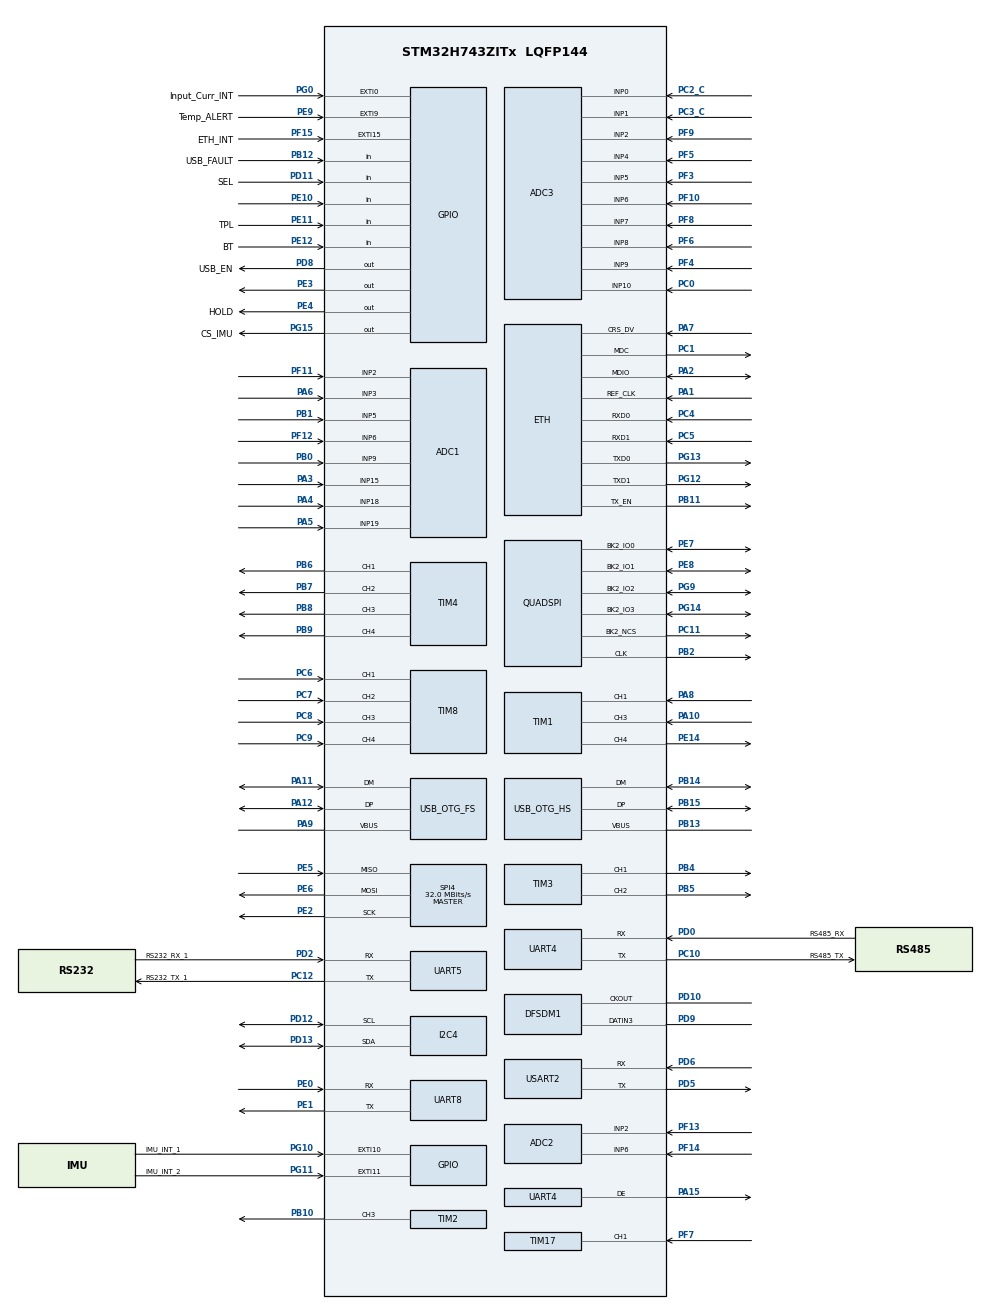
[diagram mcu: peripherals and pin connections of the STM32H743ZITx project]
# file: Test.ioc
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ADC1.Channel-13\#ChannelRegularConversion=ADC_CHANNEL_2
ADC1.NbrOfConversionFlag=1
ADC1.OffsetNumber-13\#ChannelRegularConversion=ADC_OFFSET_NONE
ADC1.OffsetSignedSaturation-13\#ChannelRegularConversion=DISABLE
ADC1.Rank-13\#ChannelRegularConversion=1
ADC1.SamplingTime-13\#ChannelRegularConversion=ADC_SAMPLETIME_1CYCLE_5
ADC1.master=1
ADC2.Channel-4\#ChannelRegularConversion=ADC_CHANNEL_2
ADC2.NbrOfConversionFlag=1
ADC2.OffsetNumber-4\#ChannelRegularConversion=ADC_OFFSET_NONE
ADC2.OffsetSignedSaturation-4\#ChannelRegularConversion=DISABLE
ADC2.Rank-4\#ChannelRegularConversion=1
ADC2.SamplingTime-4\#ChannelRegularConversion=ADC_SAMPLETIME_1CYCLE_5
ADC3.Channel-2\#ChannelRegularConversion=ADC_CHANNEL_2
ADC3.NbrOfConversionFlag=1
ADC3.OffsetNumber-2\#ChannelRegularConversion=ADC_OFFSET_NONE
ADC3.OffsetSignedSaturation-2\#ChannelRegularConversion=DISABLE
ADC3.Rank-2\#ChannelRegularConversion=1
ADC3.SamplingTime-2\#ChannelRegularConversion=ADC_SAMPLETIME_1CYCLE_5
CORTEX_M7.default_mode_Activation=1
ETH.MediaInterface=HAL_ETH_RMII_MODE
FREERTOS.Tasks01=defaultTask,24,128,StartDefaultTask,Default,NULL,Dynamic,NULL,NULL
Mcu.Family=STM32H7
Mcu.Name=STM32H743ZITx
Mcu.Package=LQFP144
NVIC.OTG_FS_IRQn=true\:5\:0\:false\:false\:true\:true\:false\:true\:true
NVIC.OTG_HS_IRQn=true\:5\:0\:false\:false\:true\:true\:false\:true\:true
NVIC.PriorityGroup=NVIC_PRIORITYGROUP_4
PA1.Mode=RMII
PA1.Signal=ETH_REF_CLK
PA10.Signal=S_TIM1_CH3
PA11.Mode=Device_Only
PA11.Signal=USB_OTG_FS_DM
PA12.Mode=Device_Only
PA12.Signal=USB_OTG_FS_DP
PA13\ (JTMS/SWDIO).Mode=Trace_Asynchronous_SW
PA13\ (JTMS/SWDIO).Signal=DEBUG_JTMS-SWDIO
PA14\ (JTCK/SWCLK).Mode=Trace_Asynchronous_SW
PA14\ (JTCK/SWCLK).Signal=DEBUG_JTCK-SWCLK
PA15\ (JTDI).Mode=Hardware Flow Control (RS485)
PA15\ (JTDI).Signal=UART4_DE
PA2.Mode=RMII
PA2.Signal=ETH_MDIO
PA3.Signal=ADCx_INP15
PA4.Signal=ADCx_INP18
PA5.Signal=ADCx_INP19
PA6.Signal=ADCx_INP3
PA7.Mode=RMII
PA7.Signal=ETH_CRS_DV
PA8.Signal=S_TIM1_CH1
PA9.Mode=Activate_VBUS
PA9.Signal=USB_OTG_FS_VBUS
PB0.Signal=ADCx_INP9
PB1.Signal=ADCx_INP5
PB10.Signal=S_TIM2_CH3
PB11.Mode=RMII
PB11.Signal=ETH_TX_EN
PB12.GPIO_Label=USB_FAULT
PB12.Signal=GPIO_Input
PB13.Mode=Activate_VBUS_FS
PB13.Signal=USB_OTG_HS_VBUS
PB14.Mode=Host_FS
PB14.Signal=USB_OTG_HS_DM
PB15.Mode=Host_FS
PB15.Signal=USB_OTG_HS_DP
PB2.Mode=Single Bank 2
PB2.Signal=QUADSPI_CLK
PB3\ (JTDO/TRACESWO).Mode=Trace_Asynchronous_SW
PB3\ (JTDO/TRACESWO).Signal=DEBUG_JTDO-SWO
PB4\ (NJTRST).Signal=S_TIM3_CH1
PB5.Signal=S_TIM3_CH2
PB6.Signal=S_TIM4_CH1
PB7.Signal=S_TIM4_CH2
PB8.Signal=S_TIM4_CH3
PB9.Signal=S_TIM4_CH4
PC0.Signal=ADCx_INP10
PC1.Mode=RMII
PC1.Signal=ETH_MDC
PC10.GPIO_Label=RS485_TX
PC10.Mode=Asynchronous
PC10.Signal=UART4_TX
PC11.Mode=Single Bank 2
PC11.Signal=QUADSPI_BK2_NCS
PC12.GPIO_Label=RS232_TX_1
PC12.Mode=Asynchronous
PC12.Signal=UART5_TX
PC14-OSC32_IN\ (OSC32_IN).Mode=LSE-External-Oscillator
PC14-OSC32_IN\ (OSC32_IN).Signal=RCC_OSC32_IN
PC15-OSC32_OUT\ (OSC32_OUT).Mode=LSE-External-Oscillator
PC15-OSC32_OUT\ (OSC32_OUT).Signal=RCC_OSC32_OUT
PC2_C.Mode=IN0-Single-Ended
PC2_C.Signal=ADC3_INP0
PC3_C.Mode=IN1-Single-Ended
PC3_C.Signal=ADC3_INP1
PC4.Mode=RMII
PC4.Signal=ETH_RXD0
PC5.Mode=RMII
PC5.Signal=ETH_RXD1
PC6.Signal=S_TIM8_CH1
PC7.Signal=S_TIM8_CH2
PC8.Signal=S_TIM8_CH3
PC9.Signal=S_TIM8_CH4
PD0.GPIO_Label=RS485_RX
PD0.Mode=Asynchronous
PD0.Signal=UART4_RX
PD10.Signal=S_CKOUTDFSDM1
PD11.GPIO_Label=SEL
PD11.Signal=GPIO_Input
PD12.Mode=I2C
PD12.Signal=I2C4_SCL
PD13.Mode=I2C
PD13.Signal=I2C4_SDA
PD2.GPIO_Label=RS232_RX_1
PD2.Mode=Asynchronous
PD2.Signal=UART5_RX
PD5.Mode=Asynchronous
PD5.Signal=USART2_TX
PD6.Mode=Asynchronous
PD6.Signal=USART2_RX
PD8.GPIO_Label=USB_EN
PD8.Signal=GPIO_Output
PD9.Signal=S_DATAIN3DFSDM1
PE0.Mode=Asynchronous
PE0.Signal=UART8_RX
PE1.Mode=Asynchronous
PE1.Signal=UART8_TX
PE10.Signal=GPIO_Input
PE11.GPIO_Label=TPL
PE11.Signal=GPIO_Input
PE12.GPIO_Label=BT
PE12.Signal=GPIO_Input
PE14.Signal=S_TIM1_CH4
PE2.Mode=Full_Duplex_Master
PE2.Signal=SPI4_SCK
PE3.Signal=GPIO_Output
PE4.GPIO_Label=HOLD
PE4.Signal=GPIO_Output
PE5.Mode=Full_Duplex_Master
PE5.Signal=SPI4_MISO
PE6.Mode=Full_Duplex_Master
PE6.Signal=SPI4_MOSI
PE7.Mode=Single Bank 2
PE7.Signal=QUADSPI_BK2_IO0
PE8.Mode=Single Bank 2
PE8.Signal=QUADSPI_BK2_IO1
PE9.GPIO_Label=Temp_ALERT
PE9.Signal=GPXTI9
PF10.Mode=IN6-Single-Ended
PF10.Signal=ADC3_INP6
PF11.Mode=IN2-Single-Ended
PF11.Signal=ADC1_INP2
PF12.Mode=IN6-Single-Ended
PF12.Signal=ADC1_INP6
PF13.Mode=IN2-Single-Ended
PF13.Signal=ADC2_INP2
PF14.Mode=IN6-Single-Ended
PF14.Signal=ADC2_INP6
PF15.GPIO_Label=ETH_INT
PF15.Signal=GPXTI15
PF3.Mode=IN5-Single-Ended
PF3.Signal=ADC3_INP5
PF4.Mode=IN9-Single-Ended
PF4.Signal=ADC3_INP9
PF5.Mode=IN4-Single-Ended
PF5.Signal=ADC3_INP4
PF6.Mode=IN8-Single-Ended
PF6.Signal=ADC3_INP8
PF7.Signal=S_TIM17_CH1
PF8.Mode=IN7-Single-Ended
PF8.Signal=ADC3_INP7
PF9.Mode=IN2-Single-Ended
PF9.Signal=ADC3_INP2
PG0.GPIO_Label=Input_Curr_INT
PG0.Signal=GPXTI0
PG10.GPIO_Label=IMU_INT_1
PG10.Signal=GPXTI10
PG11.GPIO_Label=IMU_INT_2
PG11.Signal=GPXTI11
PG12.Mode=RMII
PG12.Signal=ETH_TXD1
PG13.Mode=RMII
PG13.Signal=ETH_TXD0
PG14.Mode=Single Bank 2
PG14.Signal=QUADSPI_BK2_IO3
PG15.GPIO_Label=CS_IMU
PG15.Signal=GPIO_Output
PG9.Mode=Single Bank 2
PG9.Signal=QUADSPI_BK2_IO2
PH0-OSC_IN\ (PH0).Mode=HSE-External-Oscillator
PH0-OSC_IN\ (PH0).Signal=RCC_OSC_IN
PH1-OSC_OUT\ (PH1).Mode=HSE-External-Oscillator
PH1-OSC_OUT\ (PH1).Signal=RCC_OSC_OUT
ProjectManager.HeapSize=0x200
ProjectManager.StackSize=0x400
ProjectManager.TargetToolchain=STM32CubeIDE
RCC.ADCFreq_Value=129000000
RCC.APB1Freq_Value=64000000
RCC.APB2Freq_Value=64000000
RCC.APB3Freq_Value=64000000
RCC.APB4Freq_Value=64000000
RCC.CortexFreq_Value=64000000
RCC.HCLKFreq_Value=64000000
RCC.PLLSourceVirtualString=RCC_PLLSOURCE_HSI
RCC.SYSCLKFreq_VALUE=64000000
RCC.USBFreq_Value=129000000
SH.ADCx_INP10.0=ADC3_INP10,IN10-Single-Ended
SH.ADCx_INP15.0=ADC1_INP15,IN15-Single-Ended
SH.ADCx_INP15.1=ADC2_INP15
SH.ADCx_INP18.0=ADC1_INP18,IN18-Single-Ended
SH.ADCx_INP19.0=ADC1_INP19,IN19-Single-Ended
SH.ADCx_INP3.0=ADC1_INP3,IN3-Single-Ended
SH.ADCx_INP5.0=ADC1_INP5,IN5-Single-Ended
SH.ADCx_INP9.0=ADC1_INP9,IN9-Single-Ended
SH.S_CKOUTDFSDM1.0=DFSDM1_CKOUT,PDM_SPI_input_from_ch3_and_internal_clock
SH.S_DATAIN3DFSDM1.0=DFSDM1_DATIN3,PDM_SPI_input_from_ch3_and_internal_clock
SH.S_TIM17_CH1.0=TIM17_CH1,Input_Capture1_from_TI1
SH.S_TIM1_CH1.0=TIM1_CH1,Input_Capture1_from_TI1
SH.S_TIM1_CH3.0=TIM1_CH3,Input_Capture3_from_TI3
SH.S_TIM1_CH4.0=TIM1_CH4,PWM Generation4 CH4
SH.S_TIM2_CH3.0=TIM2_CH3,PWM Generation3 CH3
SH.S_TIM3_CH1.0=TIM3_CH1,PWM Generation1 CH1
SH.S_TIM3_CH2.0=TIM3_CH2,PWM Generation2 CH2
SH.S_TIM4_CH1.0=TIM4_CH1,PWM Generation1 CH1
SH.S_TIM4_CH2.0=TIM4_CH2,PWM Generation2 CH2
SH.S_TIM4_CH3.0=TIM4_CH3,PWM Generation3 CH3
SH.S_TIM4_CH4.0=TIM4_CH4,PWM Generation4 CH4
SH.S_TIM8_CH1.0=TIM8_CH1,Input_Capture1_from_TI1
SH.S_TIM8_CH2.0=TIM8_CH2,Input_Capture2_from_TI2
SH.S_TIM8_CH3.0=TIM8_CH3,Input_Capture3_from_TI3
SH.S_TIM8_CH4.0=TIM8_CH4,Input_Capture4_from_TI4
SPI4.CalculateBaudRate=32.0 MBits/s
SPI4.Direction=SPI_DIRECTION_2LINES
SPI4.Mode=SPI_MODE_MASTER
SPI4.VirtualType=VM_MASTER
TIM1.Channel-Input_Capture1_from_TI1=TIM_CHANNEL_1
TIM1.Channel-Input_Capture3_from_TI3=TIM_CHANNEL_3
TIM1.Channel-PWM\ Generation4\ CH4=TIM_CHANNEL_4
TIM17.Channel=TIM_CHANNEL_1
TIM2.Channel-Input_Capture4_from_TI4=TIM_CHANNEL_4
TIM2.Channel-PWM\ Generation3\ CH3=TIM_CHANNEL_3
TIM3.Channel-PWM\ Generation1\ CH1=TIM_CHANNEL_1
TIM3.Channel-PWM\ Generation2\ CH2=TIM_CHANNEL_2
TIM3.Channel-PWM\ Generation4\ CH4=TIM_CHANNEL_4
TIM4.Channel-PWM\ Generation1\ CH1=TIM_CHANNEL_1
TIM4.Channel-PWM\ Generation2\ CH2=TIM_CHANNEL_2
TIM4.Channel-PWM\ Generation3\ CH3=TIM_CHANNEL_3
TIM4.Channel-PWM\ Generation4\ CH4=TIM_CHANNEL_4
TIM8.Channel-Input_Capture1_from_TI1=TIM_CHANNEL_1
TIM8.Channel-Input_Capture2_from_TI2=TIM_CHANNEL_2
TIM8.Channel-Input_Capture3_from_TI3=TIM_CHANNEL_3
TIM8.Channel-Input_Capture4_from_TI4=TIM_CHANNEL_4
USART2.VirtualMode-Asynchronous=VM_ASYNC
USB_DEVICE.CLASS_NAME_FS=DFU
USB_DEVICE.VirtualMode-DFU_FS=Dfu
USB_DEVICE.VirtualModeFS=Dfu_FS
USB_HOST.USBH_HandleTypeDef-CDC_HS=hUsbHostHS
USB_HOST.VirtualModeHS=Cdc
USB_OTG_FS.VirtualMode=Device_Only
USB_OTG_HS.VirtualMode-Host_FS=Host_FS
VP_FREERTOS_VS_CMSIS_V2.Mode=CMSIS_V2
VP_MEMORYMAP_VS_MEMORYMAP.Mode=CurAppReg
VP_TIM17_VS_ClockSourceINT.Mode=Enable_Timer
VP_USB_DEVICE_VS_USB_DEVICE_DFU_FS.Mode=DFU_FS
VP_USB_HOST_VS_USB_HOST_CDC_HS.Mode=CDC_HS
board=custom

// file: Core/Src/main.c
/* USER CODE BEGIN Header */
/**
  ******************************************************************************
  * @file           : main.c
  * @brief          : Main program body
  ******************************************************************************
  * @attention
  *
  * Copyright (c) 2025 STMicroelectronics.
  * All rights reserved.
  *
  * This software is licensed under terms that can be found in the LICENSE file
  * in the root directory of this software component.
  * If no LICENSE file comes with this software, it is provided AS-IS.
  *
  ******************************************************************************
  */
/* USER CODE END Header */
#include "main.h"
#include "string.h"
#include "cmsis_os.h"
#include "usb_device.h"
#include "usb_host.h"

#if defined ( __ICCARM__ ) /*!< IAR Compiler */
#pragma location=0x30000000
ETH_DMADescTypeDef  DMARxDscrTab[ETH_RX_DESC_CNT]; /* Ethernet Rx DMA Descriptors */
#pragma location=0x30000080
ETH_DMADescTypeDef  DMATxDscrTab[ETH_TX_DESC_CNT]; /* Ethernet Tx DMA Descriptors */

#elif defined ( __CC_ARM )  /* MDK ARM Compiler */

__attribute__((at(0x30000000))) ETH_DMADescTypeDef  DMARxDscrTab[ETH_RX_DESC_CNT]; /* Ethernet Rx DMA Descriptors */
__attribute__((at(0x30000080))) ETH_DMADescTypeDef  DMATxDscrTab[ETH_TX_DESC_CNT]; /* Ethernet Tx DMA Descriptors */

#elif defined ( __GNUC__ ) /* GNU Compiler */

ETH_DMADescTypeDef DMARxDscrTab[ETH_RX_DESC_CNT] __attribute__((section(".RxDescripSection"))); /* Ethernet Rx DMA Descriptors */
ETH_DMADescTypeDef DMATxDscrTab[ETH_TX_DESC_CNT] __attribute__((section(".TxDescripSection")));   /* Ethernet Tx DMA Descriptors */
#endif

ETH_TxPacketConfig TxConfig;

ADC_HandleTypeDef hadc1;
ADC_HandleTypeDef hadc2;
ADC_HandleTypeDef hadc3;

ETH_HandleTypeDef heth;

I2C_HandleTypeDef hi2c4;

SPI_HandleTypeDef hspi4;

TIM_HandleTypeDef htim1;
TIM_HandleTypeDef htim2;
TIM_HandleTypeDef htim3;
TIM_HandleTypeDef htim4;
TIM_HandleTypeDef htim8;
TIM_HandleTypeDef htim17;

UART_HandleTypeDef huart4;
UART_HandleTypeDef huart5;
UART_HandleTypeDef huart8;
UART_HandleTypeDef huart2;

/* Definitions for defaultTask */
osThreadId_t defaultTaskHandle;
const osThreadAttr_t defaultTask_attributes = {
  .name = "defaultTask",
  .stack_size = 128 * 4,
  .priority = (osPriority_t) osPriorityNormal,
};

void SystemClock_Config(void);
void PeriphCommonClock_Config(void);
static void MPU_Config(void);
static void MX_GPIO_Init(void);
static void MX_ADC1_Init(void);
static void MX_ADC2_Init(void);
static void MX_ADC3_Init(void);
static void MX_ETH_Init(void);
static void MX_I2C4_Init(void);
static void MX_SPI4_Init(void);
static void MX_TIM1_Init(void);
static void MX_TIM2_Init(void);
static void MX_TIM3_Init(void);
static void MX_TIM4_Init(void);
static void MX_TIM8_Init(void);
static void MX_TIM17_Init(void);
static void MX_UART4_Init(void);
static void MX_UART5_Init(void);
static void MX_UART8_Init(void);
static void MX_USART2_UART_Init(void);
void StartDefaultTask(void *argument);

int main(void)
{

  /* MPU Configuration--------------------------------------------------------*/
  MPU_Config();

  /* MCU Configuration--------------------------------------------------------*/

  /* Reset of all peripherals, Initializes the Flash interface and the Systick. */
  HAL_Init();

  /* Configure the system clock */
  SystemClock_Config();

  /* Configure the peripherals common clocks */
  PeriphCommonClock_Config();

  /* Initialize all configured peripherals */
  MX_GPIO_Init();
  MX_ADC1_Init();
  MX_ADC2_Init();
  MX_ADC3_Init();
  MX_ETH_Init();
  MX_I2C4_Init();
  MX_SPI4_Init();
  MX_TIM1_Init();
  MX_TIM2_Init();
  MX_TIM3_Init();
  MX_TIM4_Init();
  MX_TIM8_Init();
  MX_TIM17_Init();
  MX_UART4_Init();
  MX_UART5_Init();
  MX_UART8_Init();
  MX_USART2_UART_Init();

  /* Init scheduler */
  osKernelInitialize();

  /* Create the thread(s) */
  /* creation of defaultTask */
  defaultTaskHandle = osThreadNew(StartDefaultTask, NULL, &defaultTask_attributes);

  /* Start scheduler */
  osKernelStart();

  /* We should never get here as control is now taken by the scheduler */

  /* Infinite loop */
  while (1)
  {

  }
}

void SystemClock_Config(void)
{
  RCC_OscInitTypeDef RCC_OscInitStruct = {0};
  RCC_ClkInitTypeDef RCC_ClkInitStruct = {0};

  /** Supply configuration update enable
  */
  HAL_PWREx_ConfigSupply(PWR_LDO_SUPPLY);

  /** Configure the main internal regulator output voltage
  */
  __HAL_PWR_VOLTAGESCALING_CONFIG(PWR_REGULATOR_VOLTAGE_SCALE3);

  while(!__HAL_PWR_GET_FLAG(PWR_FLAG_VOSRDY)) {}

  /** Initializes the RCC Oscillators according to the specified parameters
  * in the RCC_OscInitTypeDef structure.
  */
  RCC_OscInitStruct.OscillatorType = RCC_OSCILLATORTYPE_HSI;
  RCC_OscInitStruct.HSIState = RCC_HSI_DIV1;
  RCC_OscInitStruct.HSICalibrationValue = RCC_HSICALIBRATION_DEFAULT;
  RCC_OscInitStruct.PLL.PLLState = RCC_PLL_ON;
  RCC_OscInitStruct.PLL.PLLSource = RCC_PLLSOURCE_HSI;
  RCC_OscInitStruct.PLL.PLLM = 32;
  RCC_OscInitStruct.PLL.PLLN = 129;
  RCC_OscInitStruct.PLL.PLLP = 2;
  RCC_OscInitStruct.PLL.PLLQ = 2;
  RCC_OscInitStruct.PLL.PLLR = 2;
  RCC_OscInitStruct.PLL.PLLRGE = RCC_PLL1VCIRANGE_1;
  RCC_OscInitStruct.PLL.PLLVCOSEL = RCC_PLL1VCOWIDE;
  RCC_OscInitStruct.PLL.PLLFRACN = 0;
  if (HAL_RCC_OscConfig(&RCC_OscInitStruct) != HAL_OK)
  {
    Error_Handler();
  }

  /** Initializes the CPU, AHB and APB buses clocks
  */
  RCC_ClkInitStruct.ClockType = RCC_CLOCKTYPE_HCLK|RCC_CLOCKTYPE_SYSCLK
                              |RCC_CLOCKTYPE_PCLK1|RCC_CLOCKTYPE_PCLK2
                              |RCC_CLOCKTYPE_D3PCLK1|RCC_CLOCKTYPE_D1PCLK1;
  RCC_ClkInitStruct.SYSCLKSource = RCC_SYSCLKSOURCE_HSI;
  RCC_ClkInitStruct.SYSCLKDivider = RCC_SYSCLK_DIV1;
  RCC_ClkInitStruct.AHBCLKDivider = RCC_HCLK_DIV1;
  RCC_ClkInitStruct.APB3CLKDivider = RCC_APB3_DIV1;
  RCC_ClkInitStruct.APB1CLKDivider = RCC_APB1_DIV1;
  RCC_ClkInitStruct.APB2CLKDivider = RCC_APB2_DIV1;
  RCC_ClkInitStruct.APB4CLKDivider = RCC_APB4_DIV1;

  if (HAL_RCC_ClockConfig(&RCC_ClkInitStruct, FLASH_LATENCY_1) != HAL_OK)
  {
    Error_Handler();
  }
}

void PeriphCommonClock_Config(void)
{
  RCC_PeriphCLKInitTypeDef PeriphClkInitStruct = {0};

  /** Initializes the peripherals clock
  */
  PeriphClkInitStruct.PeriphClockSelection = RCC_PERIPHCLK_ADC;
  PeriphClkInitStruct.PLL2.PLL2M = 32;
  PeriphClkInitStruct.PLL2.PLL2N = 129;
  PeriphClkInitStruct.PLL2.PLL2P = 2;
  PeriphClkInitStruct.PLL2.PLL2Q = 2;
  PeriphClkInitStruct.PLL2.PLL2R = 2;
  PeriphClkInitStruct.PLL2.PLL2RGE = RCC_PLL2VCIRANGE_1;
  PeriphClkInitStruct.PLL2.PLL2VCOSEL = RCC_PLL2VCOWIDE;
  PeriphClkInitStruct.PLL2.PLL2FRACN = 0;
  PeriphClkInitStruct.AdcClockSelection = RCC_ADCCLKSOURCE_PLL2;
  if (HAL_RCCEx_PeriphCLKConfig(&PeriphClkInitStruct) != HAL_OK)
  {
    Error_Handler();
  }
}

static void MX_ADC1_Init(void)
{

  ADC_MultiModeTypeDef multimode = {0};
  ADC_ChannelConfTypeDef sConfig = {0};

  /** Common config
  */
  hadc1.Instance = ADC1;
  hadc1.Init.ClockPrescaler = ADC_CLOCK_ASYNC_DIV4;
  hadc1.Init.Resolution = ADC_RESOLUTION_16B;
  hadc1.Init.ScanConvMode = ADC_SCAN_DISABLE;
  hadc1.Init.EOCSelection = ADC_EOC_SINGLE_CONV;
  hadc1.Init.LowPowerAutoWait = DISABLE;
  hadc1.Init.ContinuousConvMode = DISABLE;
  hadc1.Init.NbrOfConversion = 1;
  hadc1.Init.DiscontinuousConvMode = DISABLE;
  hadc1.Init.ExternalTrigConv = ADC_SOFTWARE_START;
  hadc1.Init.ExternalTrigConvEdge = ADC_EXTERNALTRIGCONVEDGE_NONE;
  hadc1.Init.ConversionDataManagement = ADC_CONVERSIONDATA_DR;
  hadc1.Init.Overrun = ADC_OVR_DATA_PRESERVED;
  hadc1.Init.LeftBitShift = ADC_LEFTBITSHIFT_NONE;
  hadc1.Init.OversamplingMode = DISABLE;
  hadc1.Init.Oversampling.Ratio = 1;
  if (HAL_ADC_Init(&hadc1) != HAL_OK)
  {
    Error_Handler();
  }

  /** Configure the ADC multi-mode
  */
  multimode.Mode = ADC_MODE_INDEPENDENT;
  if (HAL_ADCEx_MultiModeConfigChannel(&hadc1, &multimode) != HAL_OK)
  {
    Error_Handler();
  }

  /** Configure Regular Channel
  */
  sConfig.Channel = ADC_CHANNEL_2;
  sConfig.Rank = ADC_REGULAR_RANK_1;
  sConfig.SamplingTime = ADC_SAMPLETIME_1CYCLE_5;
  sConfig.SingleDiff = ADC_SINGLE_ENDED;
  sConfig.OffsetNumber = ADC_OFFSET_NONE;
  sConfig.Offset = 0;
  sConfig.OffsetSignedSaturation = DISABLE;
  if (HAL_ADC_ConfigChannel(&hadc1, &sConfig) != HAL_OK)
  {
    Error_Handler();
  }

}

static void MX_ADC2_Init(void)
{

  ADC_ChannelConfTypeDef sConfig = {0};

  /** Common config
  */
  hadc2.Instance = ADC2;
  hadc2.Init.ClockPrescaler = ADC_CLOCK_ASYNC_DIV4;
  hadc2.Init.Resolution = ADC_RESOLUTION_16B;
  hadc2.Init.ScanConvMode = ADC_SCAN_DISABLE;
  hadc2.Init.EOCSelection = ADC_EOC_SINGLE_CONV;
  hadc2.Init.LowPowerAutoWait = DISABLE;
  hadc2.Init.ContinuousConvMode = DISABLE;
  hadc2.Init.NbrOfConversion = 1;
  hadc2.Init.DiscontinuousConvMode = DISABLE;
  hadc2.Init.ExternalTrigConv = ADC_SOFTWARE_START;
  hadc2.Init.ExternalTrigConvEdge = ADC_EXTERNALTRIGCONVEDGE_NONE;
  hadc2.Init.ConversionDataManagement = ADC_CONVERSIONDATA_DR;
  hadc2.Init.Overrun = ADC_OVR_DATA_PRESERVED;
  hadc2.Init.LeftBitShift = ADC_LEFTBITSHIFT_NONE;
  hadc2.Init.OversamplingMode = DISABLE;
  hadc2.Init.Oversampling.Ratio = 1;
  if (HAL_ADC_Init(&hadc2) != HAL_OK)
  {
    Error_Handler();
  }

  /** Configure Regular Channel
  */
  sConfig.Channel = ADC_CHANNEL_2;
  sConfig.Rank = ADC_REGULAR_RANK_1;
  sConfig.SamplingTime = ADC_SAMPLETIME_1CYCLE_5;
  sConfig.SingleDiff = ADC_SINGLE_ENDED;
  sConfig.OffsetNumber = ADC_OFFSET_NONE;
  sConfig.Offset = 0;
  sConfig.OffsetSignedSaturation = DISABLE;
  if (HAL_ADC_ConfigChannel(&hadc2, &sConfig) != HAL_OK)
  {
    Error_Handler();
  }

}

static void MX_ADC3_Init(void)
{

  ADC_ChannelConfTypeDef sConfig = {0};

  /** Common config
  */
  hadc3.Instance = ADC3;
  hadc3.Init.ClockPrescaler = ADC_CLOCK_ASYNC_DIV4;
  hadc3.Init.Resolution = ADC_RESOLUTION_16B;
  hadc3.Init.ScanConvMode = ADC_SCAN_DISABLE;
  hadc3.Init.EOCSelection = ADC_EOC_SINGLE_CONV;
  hadc3.Init.LowPowerAutoWait = DISABLE;
  hadc3.Init.ContinuousConvMode = DISABLE;
  hadc3.Init.NbrOfConversion = 1;
  hadc3.Init.DiscontinuousConvMode = DISABLE;
  hadc3.Init.ExternalTrigConv = ADC_SOFTWARE_START;
  hadc3.Init.ExternalTrigConvEdge = ADC_EXTERNALTRIGCONVEDGE_NONE;
  hadc3.Init.ConversionDataManagement = ADC_CONVERSIONDATA_DR;
  hadc3.Init.Overrun = ADC_OVR_DATA_PRESERVED;
  hadc3.Init.LeftBitShift = ADC_LEFTBITSHIFT_NONE;
  hadc3.Init.OversamplingMode = DISABLE;
  hadc3.Init.Oversampling.Ratio = 1;
  if (HAL_ADC_Init(&hadc3) != HAL_OK)
  {
    Error_Handler();
  }

  /** Configure Regular Channel
  */
  sConfig.Channel = ADC_CHANNEL_2;
  sConfig.Rank = ADC_REGULAR_RANK_1;
  sConfig.SamplingTime = ADC_SAMPLETIME_1CYCLE_5;
  sConfig.SingleDiff = ADC_SINGLE_ENDED;
  sConfig.OffsetNumber = ADC_OFFSET_NONE;
  sConfig.Offset = 0;
  sConfig.OffsetSignedSaturation = DISABLE;
  if (HAL_ADC_ConfigChannel(&hadc3, &sConfig) != HAL_OK)
  {
    Error_Handler();
  }

}

static void MX_ETH_Init(void)
{

   static uint8_t MACAddr[6];

  heth.Instance = ETH;
  MACAddr[0] = 0x00;
  MACAddr[1] = 0x80;
  MACAddr[2] = 0xE1;
  MACAddr[3] = 0x00;
  MACAddr[4] = 0x00;
  MACAddr[5] = 0x00;
  heth.Init.MACAddr = &MACAddr[0];
  heth.Init.MediaInterface = HAL_ETH_RMII_MODE;
  heth.Init.TxDesc = DMATxDscrTab;
  heth.Init.RxDesc = DMARxDscrTab;
  heth.Init.RxBuffLen = 1536;

  if (HAL_ETH_Init(&heth) != HAL_OK)
  {
    Error_Handler();
  }

  memset(&TxConfig, 0 , sizeof(ETH_TxPacketConfig));
  TxConfig.Attributes = ETH_TX_PACKETS_FEATURES_CSUM | ETH_TX_PACKETS_FEATURES_CRCPAD;
  TxConfig.ChecksumCtrl = ETH_CHECKSUM_IPHDR_PAYLOAD_INSERT_PHDR_CALC;
  TxConfig.CRCPadCtrl = ETH_CRC_PAD_INSERT;

}

static void MX_I2C4_Init(void)
{

  hi2c4.Instance = I2C4;
  hi2c4.Init.Timing = 0x10707DBC;
  hi2c4.Init.OwnAddress1 = 0;
  hi2c4.Init.AddressingMode = I2C_ADDRESSINGMODE_7BIT;
  hi2c4.Init.DualAddressMode = I2C_DUALADDRESS_DISABLE;
  hi2c4.Init.OwnAddress2 = 0;
  hi2c4.Init.OwnAddress2Masks = I2C_OA2_NOMASK;
  hi2c4.Init.GeneralCallMode = I2C_GENERALCALL_DISABLE;
  hi2c4.Init.NoStretchMode = I2C_NOSTRETCH_DISABLE;
  if (HAL_I2C_Init(&hi2c4) != HAL_OK)
  {
    Error_Handler();
  }

  /** Configure Analogue filter
  */
  if (HAL_I2CEx_ConfigAnalogFilter(&hi2c4, I2C_ANALOGFILTER_ENABLE) != HAL_OK)
  {
    Error_Handler();
  }

  /** Configure Digital filter
  */
  if (HAL_I2CEx_ConfigDigitalFilter(&hi2c4, 0) != HAL_OK)
  {
    Error_Handler();
  }

}

static void MX_SPI4_Init(void)
{

  /* SPI4 parameter configuration*/
  hspi4.Instance = SPI4;
  hspi4.Init.Mode = SPI_MODE_MASTER;
  hspi4.Init.Direction = SPI_DIRECTION_2LINES;
  hspi4.Init.DataSize = SPI_DATASIZE_4BIT;
  hspi4.Init.CLKPolarity = SPI_POLARITY_LOW;
  hspi4.Init.CLKPhase = SPI_PHASE_1EDGE;
  hspi4.Init.NSS = SPI_NSS_SOFT;
  hspi4.Init.BaudRatePrescaler = SPI_BAUDRATEPRESCALER_2;
  hspi4.Init.FirstBit = SPI_FIRSTBIT_MSB;
  hspi4.Init.TIMode = SPI_TIMODE_DISABLE;
  hspi4.Init.CRCCalculation = SPI_CRCCALCULATION_DISABLE;
  hspi4.Init.CRCPolynomial = 0x0;
  hspi4.Init.NSSPMode = SPI_NSS_PULSE_ENABLE;
  hspi4.Init.NSSPolarity = SPI_NSS_POLARITY_LOW;
  hspi4.Init.FifoThreshold = SPI_FIFO_THRESHOLD_01DATA;
  hspi4.Init.TxCRCInitializationPattern = SPI_CRC_INITIALIZATION_ALL_ZERO_PATTERN;
  hspi4.Init.RxCRCInitializationPattern = SPI_CRC_INITIALIZATION_ALL_ZERO_PATTERN;
  hspi4.Init.MasterSSIdleness = SPI_MASTER_SS_IDLENESS_00CYCLE;
  hspi4.Init.MasterInterDataIdleness = SPI_MASTER_INTERDATA_IDLENESS_00CYCLE;
  hspi4.Init.MasterReceiverAutoSusp = SPI_MASTER_RX_AUTOSUSP_DISABLE;
  hspi4.Init.MasterKeepIOState = SPI_MASTER_KEEP_IO_STATE_DISABLE;
  hspi4.Init.IOSwap = SPI_IO_SWAP_DISABLE;
  if (HAL_SPI_Init(&hspi4) != HAL_OK)
  {
    Error_Handler();
  }

}

static void MX_TIM1_Init(void)
{

  TIM_MasterConfigTypeDef sMasterConfig = {0};
  TIM_IC_InitTypeDef sConfigIC = {0};

  htim1.Instance = TIM1;
  htim1.Init.Prescaler = 0;
  htim1.Init.CounterMode = TIM_COUNTERMODE_UP;
  htim1.Init.Period = 65535;
  htim1.Init.ClockDivision = TIM_CLOCKDIVISION_DIV1;
  htim1.Init.RepetitionCounter = 0;
  htim1.Init.AutoReloadPreload = TIM_AUTORELOAD_PRELOAD_DISABLE;
  if (HAL_TIM_IC_Init(&htim1) != HAL_OK)
  {
    Error_Handler();
  }
  sMasterConfig.MasterOutputTrigger = TIM_TRGO_RESET;
  sMasterConfig.MasterOutputTrigger2 = TIM_TRGO2_RESET;
  sMasterConfig.MasterSlaveMode = TIM_MASTERSLAVEMODE_DISABLE;
  if (HAL_TIMEx_MasterConfigSynchronization(&htim1, &sMasterConfig) != HAL_OK)
  {
    Error_Handler();
  }
  sConfigIC.ICPolarity = TIM_INPUTCHANNELPOLARITY_RISING;
  sConfigIC.ICSelection = TIM_ICSELECTION_DIRECTTI;
  sConfigIC.ICPrescaler = TIM_ICPSC_DIV1;
  sConfigIC.ICFilter = 0;
  if (HAL_TIM_IC_ConfigChannel(&htim1, &sConfigIC, TIM_CHANNEL_1) != HAL_OK)
  {
    Error_Handler();
  }
  if (HAL_TIM_IC_ConfigChannel(&htim1, &sConfigIC, TIM_CHANNEL_3) != HAL_OK)
  {
    Error_Handler();
  }

}

static void MX_TIM2_Init(void)
{

  TIM_MasterConfigTypeDef sMasterConfig = {0};
  TIM_OC_InitTypeDef sConfigOC = {0};

  htim2.Instance = TIM2;
  htim2.Init.Prescaler = 0;
  htim2.Init.CounterMode = TIM_COUNTERMODE_UP;
  htim2.Init.Period = 4294967295;
  htim2.Init.ClockDivision = TIM_CLOCKDIVISION_DIV1;
  htim2.Init.AutoReloadPreload = TIM_AUTORELOAD_PRELOAD_DISABLE;
  if (HAL_TIM_PWM_Init(&htim2) != HAL_OK)
  {
    Error_Handler();
  }
  sMasterConfig.MasterOutputTrigger = TIM_TRGO_RESET;
  sMasterConfig.MasterSlaveMode = TIM_MASTERSLAVEMODE_DISABLE;
  if (HAL_TIMEx_MasterConfigSynchronization(&htim2, &sMasterConfig) != HAL_OK)
  {
    Error_Handler();
  }
  sConfigOC.OCMode = TIM_OCMODE_PWM1;
  sConfigOC.Pulse = 0;
  sConfigOC.OCPolarity = TIM_OCPOLARITY_HIGH;
  sConfigOC.OCFastMode = TIM_OCFAST_DISABLE;
  if (HAL_TIM_PWM_ConfigChannel(&htim2, &sConfigOC, TIM_CHANNEL_3) != HAL_OK)
  {
    Error_Handler();
  }
  HAL_TIM_MspPostInit(&htim2);

}

static void MX_TIM3_Init(void)
{

  TIM_MasterConfigTypeDef sMasterConfig = {0};
  TIM_OC_InitTypeDef sConfigOC = {0};

  htim3.Instance = TIM3;
  htim3.Init.Prescaler = 0;
  htim3.Init.CounterMode = TIM_COUNTERMODE_UP;
  htim3.Init.Period = 65535;
  htim3.Init.ClockDivision = TIM_CLOCKDIVISION_DIV1;
  htim3.Init.AutoReloadPreload = TIM_AUTORELOAD_PRELOAD_DISABLE;
  if (HAL_TIM_PWM_Init(&htim3) != HAL_OK)
  {
    Error_Handler();
  }
  sMasterConfig.MasterOutputTrigger = TIM_TRGO_RESET;
  sMasterConfig.MasterSlaveMode = TIM_MASTERSLAVEMODE_DISABLE;
  if (HAL_TIMEx_MasterConfigSynchronization(&htim3, &sMasterConfig) != HAL_OK)
  {
    Error_Handler();
  }
  sConfigOC.OCMode = TIM_OCMODE_PWM1;
  sConfigOC.Pulse = 0;
  sConfigOC.OCPolarity = TIM_OCPOLARITY_HIGH;
  sConfigOC.OCFastMode = TIM_OCFAST_DISABLE;
  if (HAL_TIM_PWM_ConfigChannel(&htim3, &sConfigOC, TIM_CHANNEL_1) != HAL_OK)
  {
    Error_Handler();
  }
  if (HAL_TIM_PWM_ConfigChannel(&htim3, &sConfigOC, TIM_CHANNEL_2) != HAL_OK)
  {
    Error_Handler();
  }
  HAL_TIM_MspPostInit(&htim3);

}

static void MX_TIM4_Init(void)
{

  TIM_MasterConfigTypeDef sMasterConfig = {0};
  TIM_OC_InitTypeDef sConfigOC = {0};

  htim4.Instance = TIM4;
  htim4.Init.Prescaler = 0;
  htim4.Init.CounterMode = TIM_COUNTERMODE_UP;
  htim4.Init.Period = 65535;
  htim4.Init.ClockDivision = TIM_CLOCKDIVISION_DIV1;
  htim4.Init.AutoReloadPreload = TIM_AUTORELOAD_PRELOAD_DISABLE;
  if (HAL_TIM_PWM_Init(&htim4) != HAL_OK)
  {
    Error_Handler();
  }
  sMasterConfig.MasterOutputTrigger = TIM_TRGO_RESET;
  sMasterConfig.MasterSlaveMode = TIM_MASTERSLAVEMODE_DISABLE;
  if (HAL_TIMEx_MasterConfigSynchronization(&htim4, &sMasterConfig) != HAL_OK)
  {
    Error_Handler();
  }
  sConfigOC.OCMode = TIM_OCMODE_PWM1;
  sConfigOC.Pulse = 0;
  sConfigOC.OCPolarity = TIM_OCPOLARITY_HIGH;
  sConfigOC.OCFastMode = TIM_OCFAST_DISABLE;
  if (HAL_TIM_PWM_ConfigChannel(&htim4, &sConfigOC, TIM_CHANNEL_1) != HAL_OK)
  {
    Error_Handler();
  }
  if (HAL_TIM_PWM_ConfigChannel(&htim4, &sConfigOC, TIM_CHANNEL_2) != HAL_OK)
  {
    Error_Handler();
  }
  if (HAL_TIM_PWM_ConfigChannel(&htim4, &sConfigOC, TIM_CHANNEL_3) != HAL_OK)
  {
    Error_Handler();
  }
  if (HAL_TIM_PWM_ConfigChannel(&htim4, &sConfigOC, TIM_CHANNEL_4) != HAL_OK)
  {
    Error_Handler();
  }
  HAL_TIM_MspPostInit(&htim4);

}

static void MX_TIM8_Init(void)
{

  TIM_MasterConfigTypeDef sMasterConfig = {0};
  TIM_IC_InitTypeDef sConfigIC = {0};

  htim8.Instance = TIM8;
  htim8.Init.Prescaler = 0;
  htim8.Init.CounterMode = TIM_COUNTERMODE_UP;
  htim8.Init.Period = 65535;
  htim8.Init.ClockDivision = TIM_CLOCKDIVISION_DIV1;
  htim8.Init.RepetitionCounter = 0;
  htim8.Init.AutoReloadPreload = TIM_AUTORELOAD_PRELOAD_DISABLE;
  if (HAL_TIM_IC_Init(&htim8) != HAL_OK)
  {
    Error_Handler();
  }
  sMasterConfig.MasterOutputTrigger = TIM_TRGO_RESET;
  sMasterConfig.MasterOutputTrigger2 = TIM_TRGO2_RESET;
  sMasterConfig.MasterSlaveMode = TIM_MASTERSLAVEMODE_DISABLE;
  if (HAL_TIMEx_MasterConfigSynchronization(&htim8, &sMasterConfig) != HAL_OK)
  {
    Error_Handler();
  }
  sConfigIC.ICPolarity = TIM_INPUTCHANNELPOLARITY_RISING;
  sConfigIC.ICSelection = TIM_ICSELECTION_DIRECTTI;
  sConfigIC.ICPrescaler = TIM_ICPSC_DIV1;
  sConfigIC.ICFilter = 0;
  if (HAL_TIM_IC_ConfigChannel(&htim8, &sConfigIC, TIM_CHANNEL_1) != HAL_OK)
  {
    Error_Handler();
  }
  if (HAL_TIM_IC_ConfigChannel(&htim8, &sConfigIC, TIM_CHANNEL_2) != HAL_OK)
  {
    Error_Handler();
  }
  if (HAL_TIM_IC_ConfigChannel(&htim8, &sConfigIC, TIM_CHANNEL_3) != HAL_OK)
  {
    Error_Handler();
  }
  if (HAL_TIM_IC_ConfigChannel(&htim8, &sConfigIC, TIM_CHANNEL_4) != HAL_OK)
  {
    Error_Handler();
  }

}

static void MX_TIM17_Init(void)
{

  htim17.Instance = TIM17;
  htim17.Init.Prescaler = 0;
  htim17.Init.CounterMode = TIM_COUNTERMODE_UP;
  htim17.Init.Period = 65535;
  htim17.Init.ClockDivision = TIM_CLOCKDIVISION_DIV1;
  htim17.Init.RepetitionCounter = 0;
  htim17.Init.AutoReloadPreload = TIM_AUTORELOAD_PRELOAD_DISABLE;
  if (HAL_TIM_Base_Init(&htim17) != HAL_OK)
  {
    Error_Handler();
  }

}

static void MX_UART4_Init(void)
{

  huart4.Instance = UART4;
  huart4.Init.BaudRate = 115200;
  huart4.Init.WordLength = UART_WORDLENGTH_8B;
  huart4.Init.StopBits = UART_STOPBITS_1;
  huart4.Init.Parity = UART_PARITY_NONE;
  huart4.Init.Mode = UART_MODE_TX_RX;
  huart4.Init.HwFlowCtl = UART_HWCONTROL_NONE;
  huart4.Init.OverSampling = UART_OVERSAMPLING_16;
  huart4.Init.OneBitSampling = UART_ONE_BIT_SAMPLE_DISABLE;
  huart4.Init.ClockPrescaler = UART_PRESCALER_DIV1;
  huart4.AdvancedInit.AdvFeatureInit = UART_ADVFEATURE_NO_INIT;
  if (HAL_RS485Ex_Init(&huart4, UART_DE_POLARITY_HIGH, 0, 0) != HAL_OK)
  {
    Error_Handler();
  }
  if (HAL_UARTEx_SetTxFifoThreshold(&huart4, UART_TXFIFO_THRESHOLD_1_8) != HAL_OK)
  {
    Error_Handler();
  }
  if (HAL_UARTEx_SetRxFifoThreshold(&huart4, UART_RXFIFO_THRESHOLD_1_8) != HAL_OK)
  {
    Error_Handler();
  }
  if (HAL_UARTEx_DisableFifoMode(&huart4) != HAL_OK)
  {
    Error_Handler();
  }

}

static void MX_UART5_Init(void)
{

  huart5.Instance = UART5;
  huart5.Init.BaudRate = 115200;
  huart5.Init.WordLength = UART_WORDLENGTH_8B;
  huart5.Init.StopBits = UART_STOPBITS_1;
  huart5.Init.Parity = UART_PARITY_NONE;
  huart5.Init.Mode = UART_MODE_TX_RX;
  huart5.Init.HwFlowCtl = UART_HWCONTROL_NONE;
  huart5.Init.OverSampling = UART_OVERSAMPLING_16;
  huart5.Init.OneBitSampling = UART_ONE_BIT_SAMPLE_DISABLE;
  huart5.Init.ClockPrescaler = UART_PRESCALER_DIV1;
  huart5.AdvancedInit.AdvFeatureInit = UART_ADVFEATURE_NO_INIT;
  if (HAL_UART_Init(&huart5) != HAL_OK)
  {
    Error_Handler();
  }
  if (HAL_UARTEx_SetTxFifoThreshold(&huart5, UART_TXFIFO_THRESHOLD_1_8) != HAL_OK)
  {
    Error_Handler();
  }
  if (HAL_UARTEx_SetRxFifoThreshold(&huart5, UART_RXFIFO_THRESHOLD_1_8) != HAL_OK)
  {
    Error_Handler();
  }
  if (HAL_UARTEx_DisableFifoMode(&huart5) != HAL_OK)
  {
    Error_Handler();
  }

}

static void MX_UART8_Init(void)
{

  huart8.Instance = UART8;
  huart8.Init.BaudRate = 115200;
  huart8.Init.WordLength = UART_WORDLENGTH_8B;
  huart8.Init.StopBits = UART_STOPBITS_1;
  huart8.Init.Parity = UART_PARITY_NONE;
  huart8.Init.Mode = UART_MODE_TX_RX;
  huart8.Init.HwFlowCtl = UART_HWCONTROL_NONE;
  huart8.Init.OverSampling = UART_OVERSAMPLING_16;
  huart8.Init.OneBitSampling = UART_ONE_BIT_SAMPLE_DISABLE;
  huart8.Init.ClockPrescaler = UART_PRESCALER_DIV1;
  huart8.AdvancedInit.AdvFeatureInit = UART_ADVFEATURE_NO_INIT;
  if (HAL_UART_Init(&huart8) != HAL_OK)
  {
    Error_Handler();
  }
  if (HAL_UARTEx_SetTxFifoThreshold(&huart8, UART_TXFIFO_THRESHOLD_1_8) != HAL_OK)
  {
    Error_Handler();
  }
  if (HAL_UARTEx_SetRxFifoThreshold(&huart8, UART_RXFIFO_THRESHOLD_1_8) != HAL_OK)
  {
    Error_Handler();
  }
  if (HAL_UARTEx_DisableFifoMode(&huart8) != HAL_OK)
  {
    Error_Handler();
  }

}

static void MX_USART2_UART_Init(void)
{

  huart2.Instance = USART2;
  huart2.Init.BaudRate = 115200;
  huart2.Init.WordLength = UART_WORDLENGTH_8B;
  huart2.Init.StopBits = UART_STOPBITS_1;
  huart2.Init.Parity = UART_PARITY_NONE;
  huart2.Init.Mode = UART_MODE_TX_RX;
  huart2.Init.HwFlowCtl = UART_HWCONTROL_NONE;
  huart2.Init.OverSampling = UART_OVERSAMPLING_16;
  huart2.Init.OneBitSampling = UART_ONE_BIT_SAMPLE_DISABLE;
  huart2.Init.ClockPrescaler = UART_PRESCALER_DIV1;
  huart2.AdvancedInit.AdvFeatureInit = UART_ADVFEATURE_NO_INIT;
  if (HAL_UART_Init(&huart2) != HAL_OK)
  {
    Error_Handler();
  }
  if (HAL_UARTEx_SetTxFifoThreshold(&huart2, UART_TXFIFO_THRESHOLD_1_8) != HAL_OK)
  {
    Error_Handler();
  }
  if (HAL_UARTEx_SetRxFifoThreshold(&huart2, UART_RXFIFO_THRESHOLD_1_8) != HAL_OK)
  {
    Error_Handler();
  }
  if (HAL_UARTEx_DisableFifoMode(&huart2) != HAL_OK)
  {
    Error_Handler();
  }

}

static void MX_GPIO_Init(void)
{
  GPIO_InitTypeDef GPIO_InitStruct = {0};

  /* GPIO Ports Clock Enable */
  __HAL_RCC_GPIOE_CLK_ENABLE();
  __HAL_RCC_GPIOC_CLK_ENABLE();
  __HAL_RCC_GPIOF_CLK_ENABLE();
  __HAL_RCC_GPIOH_CLK_ENABLE();
  __HAL_RCC_GPIOA_CLK_ENABLE();
  __HAL_RCC_GPIOB_CLK_ENABLE();
  __HAL_RCC_GPIOG_CLK_ENABLE();
  __HAL_RCC_GPIOD_CLK_ENABLE();

  /*Configure GPIO pin Output Level */
  HAL_GPIO_WritePin(GPIOE, CS_Pin|HOLD_Pin, GPIO_PIN_RESET);

  /*Configure GPIO pin Output Level */
  HAL_GPIO_WritePin(USB_EN_GPIO_Port, USB_EN_Pin, GPIO_PIN_RESET);

  /*Configure GPIO pins : CS_Pin HOLD_Pin */
  GPIO_InitStruct.Pin = CS_Pin|HOLD_Pin;
  GPIO_InitStruct.Mode = GPIO_MODE_OUTPUT_PP;
  GPIO_InitStruct.Pull = GPIO_NOPULL;
  GPIO_InitStruct.Speed = GPIO_SPEED_FREQ_LOW;
  HAL_GPIO_Init(GPIOE, &GPIO_InitStruct);

  /*Configure GPIO pin : ETH_INT_Pin */
  GPIO_InitStruct.Pin = ETH_INT_Pin;
  GPIO_InitStruct.Mode = GPIO_MODE_IT_RISING;
  GPIO_InitStruct.Pull = GPIO_NOPULL;
  HAL_GPIO_Init(ETH_INT_GPIO_Port, &GPIO_InitStruct);

  /*Configure GPIO pin : Input_Curr_INT_Pin */
  GPIO_InitStruct.Pin = Input_Curr_INT_Pin;
  GPIO_InitStruct.Mode = GPIO_MODE_IT_RISING;
  GPIO_InitStruct.Pull = GPIO_NOPULL;
  HAL_GPIO_Init(Input_Curr_INT_GPIO_Port, &GPIO_InitStruct);

  /*Configure GPIO pin : Temp_ALERT_Pin */
  GPIO_InitStruct.Pin = Temp_ALERT_Pin;
  GPIO_InitStruct.Mode = GPIO_MODE_IT_RISING;
  GPIO_InitStruct.Pull = GPIO_NOPULL;
  HAL_GPIO_Init(Temp_ALERT_GPIO_Port, &GPIO_InitStruct);

  /*Configure GPIO pins : TPH_Pin TPL_Pin BT_Pin */
  GPIO_InitStruct.Pin = TPH_Pin|TPL_Pin|BT_Pin;
  GPIO_InitStruct.Mode = GPIO_MODE_INPUT;
  GPIO_InitStruct.Pull = GPIO_NOPULL;
  HAL_GPIO_Init(GPIOE, &GPIO_InitStruct);

  /*Configure GPIO pin : USB_FAULT_Pin */
  GPIO_InitStruct.Pin = USB_FAULT_Pin;
  GPIO_InitStruct.Mode = GPIO_MODE_INPUT;
  GPIO_InitStruct.Pull = GPIO_NOPULL;
  HAL_GPIO_Init(USB_FAULT_GPIO_Port, &GPIO_InitStruct);

  /*Configure GPIO pin : USB_EN_Pin */
  GPIO_InitStruct.Pin = USB_EN_Pin;
  GPIO_InitStruct.Mode = GPIO_MODE_OUTPUT_PP;
  GPIO_InitStruct.Pull = GPIO_NOPULL;
  GPIO_InitStruct.Speed = GPIO_SPEED_FREQ_LOW;
  HAL_GPIO_Init(USB_EN_GPIO_Port, &GPIO_InitStruct);

}

void StartDefaultTask(void *argument)
{
  /* init code for USB_DEVICE */
  MX_USB_DEVICE_Init();

  /* init code for USB_HOST */
  MX_USB_HOST_Init();
  for(;;)
  {
    osDelay(1);
  }
}

 /* MPU Configuration */

void MPU_Config(void)
{
  MPU_Region_InitTypeDef MPU_InitStruct = {0};

  /* Disables the MPU */
  HAL_MPU_Disable();

  /** Initializes and configures the Region and the memory to be protected
  */
  MPU_InitStruct.Enable = MPU_REGION_ENABLE;
  MPU_InitStruct.Number = MPU_REGION_NUMBER0;
  MPU_InitStruct.BaseAddress = 0x0;
  MPU_InitStruct.Size = MPU_REGION_SIZE_4GB;
  MPU_InitStruct.SubRegionDisable = 0x87;
  MPU_InitStruct.TypeExtField = MPU_TEX_LEVEL0;
  MPU_InitStruct.AccessPermission = MPU_REGION_NO_ACCESS;
  MPU_InitStruct.DisableExec = MPU_INSTRUCTION_ACCESS_DISABLE;
  MPU_InitStruct.IsShareable = MPU_ACCESS_SHAREABLE;
  MPU_InitStruct.IsCacheable = MPU_ACCESS_NOT_CACHEABLE;
  MPU_InitStruct.IsBufferable = MPU_ACCESS_NOT_BUFFERABLE;

  HAL_MPU_ConfigRegion(&MPU_InitStruct);
  /* Enables the MPU */
  HAL_MPU_Enable(MPU_PRIVILEGED_DEFAULT);

}

void Error_Handler(void)
{
  __disable_irq();
  while (1)
  {
  }
}
